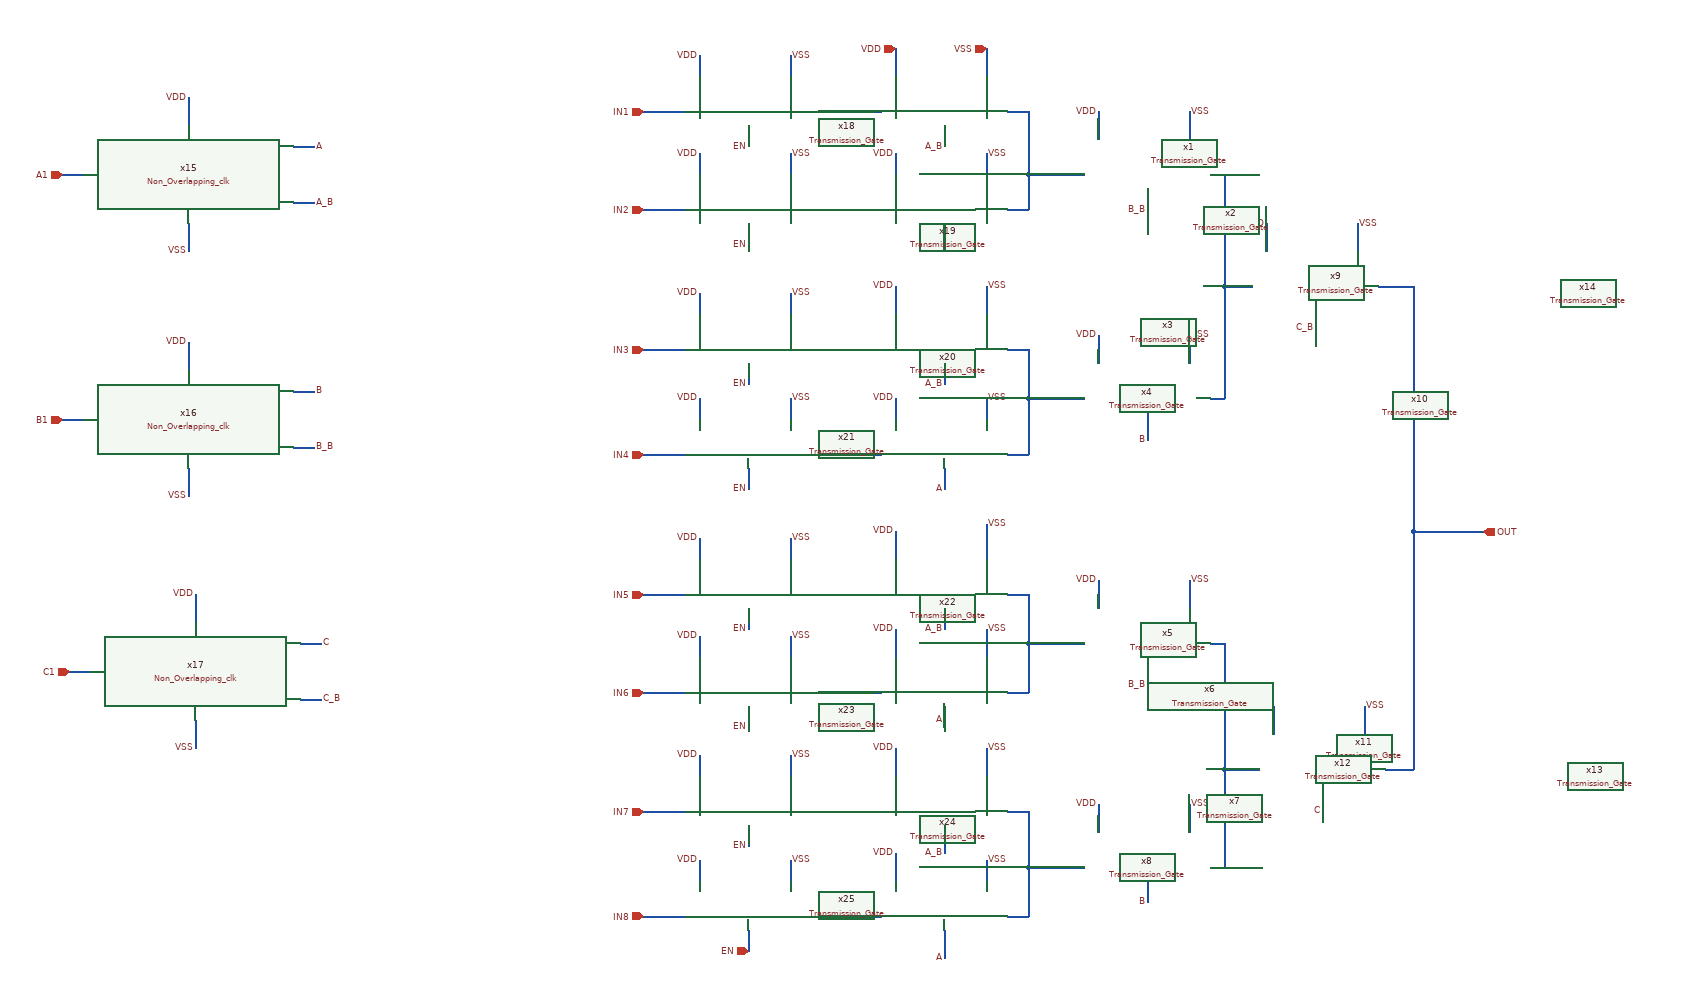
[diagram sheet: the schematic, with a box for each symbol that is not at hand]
v {xschem version=3.1.0 file_version=1.2
}
G {}
K {}
V {}
S {}
E {}
N -810 -1250 -750 -1250 {
lab=IN1}
N -450 -1340 -450 -1300 {
lab=VDD}
N -320 -1340 -320 -1300 {
lab=VSS}
N -450 -1190 -450 -1160 {
lab=VDD}
N -320 -1190 -320 -1160 {
lab=VSS}
N -450 -1000 -450 -960 {
lab=VDD}
N -320 -1000 -320 -960 {
lab=VSS}
N -450 -840 -450 -810 {
lab=VDD}
N -320 -840 -320 -810 {
lab=VSS}
N -380 -1230 -380 -1200 {
lab=A_B}
N -380 -1090 -380 -1050 {
lab=A}
N -380 -890 -380 -860 {
lab=A_B}
N -380 -740 -380 -710 {
lab=A}
N -290 -1250 -260 -1250 {
lab=#net1}
N -290 -1110 -260 -1110 {
lab=#net1}
N -260 -1160 -260 -1110 {
lab=#net1}
N -260 -1160 -180 -1160 {
lab=#net1}
N -290 -910 -260 -910 {
lab=#net2}
N -260 -840 -260 -760 {
lab=#net2}
N -290 -760 -260 -760 {
lab=#net2}
N 0 -1160 20 -1160 {
lab=#net3}
N 20 -1000 20 -840 {
lab=#net3}
N 0 -840 20 -840 {
lab=#net3}
N 20 -1000 60 -1000 {
lab=#net3}
N -290 -560 -260 -560 {
lab=#net4}
N -260 -490 -260 -420 {
lab=#net4}
N -290 -420 -260 -420 {
lab=#net4}
N -260 -490 -180 -490 {
lab=#net4}
N 0 -490 20 -490 {
lab=#net5}
N 20 -310 20 -170 {
lab=#net5}
N 0 -170 20 -170 {
lab=#net5}
N 20 -310 70 -310 {
lab=#net5}
N -290 -250 -260 -250 {
lab=#net6}
N -260 -170 -260 -100 {
lab=#net6}
N -290 -100 -260 -100 {
lab=#net6}
N -260 -170 -180 -170 {
lab=#net6}
N 240 -1000 290 -1000 {
lab=OUT}
N 290 -650 290 -310 {
lab=OUT}
N 250 -310 290 -310 {
lab=OUT}
N 290 -650 390 -650 {
lab=OUT}
N -450 -650 -450 -610 {
lab=VDD}
N -320 -660 -320 -610 {
lab=VSS}
N -380 -540 -380 -510 {
lab=A_B}
N -450 -510 -450 -470 {
lab=VDD}
N -320 -510 -320 -470 {
lab=VSS}
N -380 -400 -380 -370 {
lab=A}
N -450 -340 -450 -300 {
lab=VDD}
N -320 -340 -320 -300 {
lab=VSS}
N -380 -230 -380 -190 {
lab=A_B}
N -380 -80 -380 -40 {
lab=A}
N -450 -190 -450 -150 {
lab=VDD}
N -320 -180 -320 -150 {
lab=VSS}
N -30 -260 -30 -220 {
lab=VSS}
N -160 -260 -160 -220 {
lab=VDD}
N -90 -150 -90 -120 {
lab=B}
N -90 -470 -90 -430 {
lab=B_B}
N -160 -580 -160 -540 {
lab=VDD}
N -30 -580 -30 -540 {
lab=VSS}
N 90 -400 90 -360 {
lab=VDD}
N 220 -400 220 -360 {
lab=VSS}
N 160 -290 160 -250 {
lab=C}
N -160 -1250 -160 -1210 {
lab=VDD}
N -30 -1250 -30 -1210 {
lab=VSS}
N -90 -1140 -90 -1110 {
lab=B_B}
N 80 -1090 80 -1050 {
lab=VDD}
N 210 -1090 210 -1050 {
lab=VSS}
N 150 -980 150 -940 {
lab=C_B}
N -30 -930 -30 -890 {
lab=VSS}
N -160 -930 -160 -890 {
lab=VDD}
N -90 -820 -90 -780 {
lab=B}
N -810 -1110 -750 -1110 {
lab=IN2}
N -810 -910 -750 -910 {
lab=IN3}
N -1460 -1270 -1460 -1230 {
lab=VDD}
N -1460 -1090 -1460 -1050 {
lab=VSS}
N -1310 -1200 -1280 -1200 {
lab=A}
N -1310 -1120 -1280 -1120 {
lab=A_B}
N -1640 -1160 -1610 -1160 {
lab=A1}
N -1460 -920 -1460 -880 {
lab=VDD}
N -1460 -740 -1460 -700 {
lab=VSS}
N -1310 -850 -1280 -850 {
lab=B}
N -1310 -770 -1280 -770 {
lab=B_B}
N -1640 -810 -1610 -810 {
lab=B1}
N -1450 -560 -1450 -520 {
lab=VDD}
N -1450 -380 -1450 -340 {
lab=VSS}
N -1300 -490 -1270 -490 {
lab=C}
N -1300 -410 -1270 -410 {
lab=C_B}
N -1630 -450 -1600 -450 {
lab=C1}
N -810 -760 -750 -760 {
lab=IN4}
N -260 -1250 -260 -1160 {
lab=#net1}
N -260 -910 -260 -840 {
lab=#net2}
N -260 -840 -180 -840 {
lab=#net2}
N 20 -1160 20 -1000 {
lab=#net3}
N -260 -560 -260 -490 {
lab=#net4}
N 20 -490 20 -310 {
lab=#net5}
N -260 -250 -260 -170 {
lab=#net6}
N 290 -1000 290 -650 {
lab=OUT}
N -570 -1250 -470 -1250 {
lab=#net7}
N -730 -1330 -730 -1300 {
lab=VDD}
N -600 -1330 -600 -1300 {
lab=VSS}
N -660 -1230 -660 -1200 {
lab=EN}
N -570 -1110 -470 -1110 {
lab=#net8}
N -730 -1190 -730 -1160 {
lab=VDD}
N -600 -1190 -600 -1160 {
lab=VSS}
N -660 -1090 -660 -1060 {
lab=EN}
N -570 -910 -470 -910 {
lab=#net9}
N -730 -990 -730 -960 {
lab=VDD}
N -600 -990 -600 -960 {
lab=VSS}
N -660 -890 -660 -860 {
lab=EN}
N -570 -760 -470 -760 {
lab=#net10}
N -730 -840 -730 -810 {
lab=VDD}
N -600 -840 -600 -810 {
lab=VSS}
N -660 -740 -660 -710 {
lab=EN}
N -570 -560 -470 -560 {
lab=#net11}
N -730 -640 -730 -610 {
lab=VDD}
N -600 -640 -600 -610 {
lab=VSS}
N -660 -540 -660 -510 {
lab=EN}
N -570 -420 -470 -420 {
lab=#net12}
N -730 -500 -730 -470 {
lab=VDD}
N -600 -500 -600 -470 {
lab=VSS}
N -660 -400 -660 -370 {
lab=EN}
N -570 -250 -470 -250 {
lab=#net13}
N -730 -330 -730 -300 {
lab=VDD}
N -600 -330 -600 -300 {
lab=VSS}
N -660 -230 -660 -200 {
lab=EN}
N -570 -100 -470 -100 {
lab=#net14}
N -730 -180 -730 -150 {
lab=VDD}
N -600 -180 -600 -150 {
lab=VSS}
N -660 -80 -660 -50 {
lab=IN8}
N -810 -560 -750 -560 {
lab=IN5}
N -810 -420 -750 -420 {
lab=IN6}
N -810 -250 -750 -250 {
lab=IN7}
N -810 -100 -750 -100 {
lab=IN8}
C {devices/lab_pin.sym} -450 -1190 0 0 {name=p3 sig_type=std_logic lab=VDD}
C {devices/lab_pin.sym} -450 -1000 0 0 {name=p4 sig_type=std_logic lab=VDD}
C {devices/lab_pin.sym} -160 -1250 0 0 {name=p5 sig_type=std_logic lab=VDD}
C {devices/lab_pin.sym} -450 -840 0 0 {name=p6 sig_type=std_logic lab=VDD}
C {devices/lab_pin.sym} -450 -650 0 0 {name=p7 sig_type=std_logic lab=VDD}
C {devices/lab_pin.sym} -160 -580 0 0 {name=p8 sig_type=std_logic lab=VDD}
C {devices/lab_pin.sym} -450 -510 0 0 {name=p9 sig_type=std_logic lab=VDD}
C {devices/lab_pin.sym} -450 -340 0 0 {name=p10 sig_type=std_logic lab=VDD}
C {devices/lab_pin.sym} -450 -190 0 0 {name=p11 sig_type=std_logic lab=VDD}
C {devices/lab_pin.sym} -160 -260 0 0 {name=p12 sig_type=std_logic lab=VDD}
C {devices/lab_pin.sym} 90 -400 0 0 {name=p13 sig_type=std_logic lab=VDD}
C {devices/lab_pin.sym} -160 -930 0 0 {name=p14 sig_type=std_logic lab=VDD}
C {devices/lab_pin.sym} 80 -1090 0 0 {name=p15 sig_type=std_logic lab=VDD}
C {devices/lab_pin.sym} -320 -1190 2 0 {name=p16 sig_type=std_logic lab=VSS}
C {devices/lab_pin.sym} -30 -1250 2 0 {name=p17 sig_type=std_logic lab=VSS}
C {devices/lab_pin.sym} 210 -1090 2 0 {name=p18 sig_type=std_logic lab=VSS}
C {devices/lab_pin.sym} -30 -930 2 0 {name=p19 sig_type=std_logic lab=VSS}
C {devices/lab_pin.sym} -320 -1000 2 0 {name=p20 sig_type=std_logic lab=VSS}
C {devices/lab_pin.sym} -320 -840 2 0 {name=p21 sig_type=std_logic lab=VSS}
C {devices/lab_pin.sym} -320 -660 2 0 {name=p22 sig_type=std_logic lab=VSS}
C {devices/lab_pin.sym} -30 -580 2 0 {name=p23 sig_type=std_logic lab=VSS}
C {devices/lab_pin.sym} -320 -510 2 0 {name=p24 sig_type=std_logic lab=VSS}
C {devices/lab_pin.sym} 220 -400 2 0 {name=p25 sig_type=std_logic lab=VSS}
C {devices/lab_pin.sym} -320 -340 2 0 {name=p26 sig_type=std_logic lab=VSS}
C {devices/lab_pin.sym} -320 -180 2 0 {name=p27 sig_type=std_logic lab=VSS}
C {devices/lab_pin.sym} -30 -260 2 0 {name=p28 sig_type=std_logic lab=VSS}
C {devices/lab_pin.sym} -1460 -1270 1 0 {name=p29 sig_type=std_logic lab=VDD}
C {devices/lab_pin.sym} -1460 -1050 3 0 {name=p30 sig_type=std_logic lab=VSS}
C {devices/lab_pin.sym} -1460 -920 1 0 {name=p31 sig_type=std_logic lab=VDD}
C {devices/lab_pin.sym} -1460 -700 3 0 {name=p32 sig_type=std_logic lab=VSS}
C {devices/lab_pin.sym} -1450 -560 1 0 {name=p33 sig_type=std_logic lab=VDD}
C {devices/lab_pin.sym} -1450 -340 3 0 {name=p34 sig_type=std_logic lab=VSS}
C {devices/opin.sym} 390 -650 0 0 {name=p35 lab=OUT}
C {devices/iopin.sym} -450 -1340 2 0 {name=p1 lab=VDD}
C {devices/iopin.sym} -320 -1340 0 0 {name=p2 lab=VSS}
C {devices/ipin.sym} -810 -1250 0 0 {name=p36 lab=IN1}
C {devices/ipin.sym} -810 -1110 0 0 {name=p37 lab=IN2}
C {devices/ipin.sym} -810 -910 0 0 {name=p38 lab=IN3
}
C {devices/ipin.sym} -810 -760 0 0 {name=p39 lab=IN4}
C {devices/ipin.sym} -810 -560 0 0 {name=p40 lab=IN5}
C {devices/ipin.sym} -810 -420 0 0 {name=p41 lab=IN6}
C {devices/ipin.sym} -810 -250 0 0 {name=p42 lab=IN7}
C {devices/ipin.sym} -810 -100 0 0 {name=p43 lab=IN8}
C {devices/ipin.sym} -1640 -1160 0 0 {name=p44 lab=A1
}
C {devices/ipin.sym} -1640 -810 0 0 {name=p45 lab=B1}
C {devices/ipin.sym} -1630 -450 0 0 {name=p46 lab=C1}
C {devices/lab_pin.sym} -380 -1200 3 0 {name=p53 sig_type=std_logic lab=A_B}
C {devices/lab_pin.sym} -380 -1060 3 0 {name=p54 sig_type=std_logic lab=A}
C {devices/lab_pin.sym} -90 -780 3 0 {name=p57 sig_type=std_logic lab=B}
C {devices/lab_pin.sym} -90 -1110 3 0 {name=p58 sig_type=std_logic lab=B_B}
C {devices/lab_pin.sym} 150 -940 3 0 {name=p59 sig_type=std_logic lab=C_B}
C {devices/lab_pin.sym} 160 -250 3 0 {name=p63 sig_type=std_logic lab=C}
C {devices/lab_pin.sym} -380 -860 3 0 {name=p55 sig_type=std_logic lab=A_B}
C {devices/lab_pin.sym} -380 -710 3 0 {name=p56 sig_type=std_logic lab=A}
C {devices/lab_pin.sym} -380 -510 3 0 {name=p60 sig_type=std_logic lab=A_B}
C {devices/lab_pin.sym} -380 -380 3 0 {name=p61 sig_type=std_logic lab=A}
C {devices/lab_pin.sym} -380 -190 3 0 {name=p65 sig_type=std_logic lab=A_B}
C {devices/lab_pin.sym} -90 -120 3 0 {name=p62 sig_type=std_logic lab=B}
C {devices/lab_pin.sym} -90 -430 3 0 {name=p64 sig_type=std_logic lab=B_B}
C {devices/lab_pin.sym} -1280 -1200 2 0 {name=p47 sig_type=std_logic lab=A}
C {devices/lab_pin.sym} -1280 -1120 2 0 {name=p48 sig_type=std_logic lab=A_B}
C {devices/lab_pin.sym} -1280 -850 2 0 {name=p49 sig_type=std_logic lab=B}
C {devices/lab_pin.sym} -1280 -770 2 0 {name=p50 sig_type=std_logic lab=B_B}
C {devices/lab_pin.sym} -1270 -410 2 0 {name=p52 sig_type=std_logic lab=C_B}
C {devices/lab_pin.sym} -1270 -490 2 0 {name=p67 sig_type=std_logic lab=C}
C {devices/lab_pin.sym} -380 -40 3 0 {name=p51 sig_type=std_logic lab=A}
C {/home/shahid/GF180Projects/Tapeout/Xschem/Logic_Gates/Transmission_Gate.sym} 10 -1240 0 0 {name=x1}
C {/home/shahid/GF180Projects/Tapeout/Xschem/Logic_Gates/Transmission_Gate.sym} 10 -1100 0 0 {name=x2}
C {/home/shahid/GF180Projects/Tapeout/Xschem/Logic_Gates/Transmission_Gate.sym} 10 -900 0 0 {name=x3}
C {/home/shahid/GF180Projects/Tapeout/Xschem/Logic_Gates/Transmission_Gate.sym} 10 -750 0 0 {name=x4}
C {/home/shahid/GF180Projects/Tapeout/Xschem/Logic_Gates/Transmission_Gate.sym} 10 -550 0 0 {name=x5}
C {/home/shahid/GF180Projects/Tapeout/Xschem/Logic_Gates/Transmission_Gate.sym} 10 -410 0 0 {name=x6}
C {/home/shahid/GF180Projects/Tapeout/Xschem/Logic_Gates/Transmission_Gate.sym} 10 -240 0 0 {name=x7}
C {/home/shahid/GF180Projects/Tapeout/Xschem/Logic_Gates/Transmission_Gate.sym} 10 -90 0 0 {name=x8}
C {/home/shahid/GF180Projects/Tapeout/Xschem/Logic_Gates/Transmission_Gate.sym} 300 -1150 0 0 {name=x9}
C {/home/shahid/GF180Projects/Tapeout/Xschem/Logic_Gates/Transmission_Gate.sym} 300 -830 0 0 {name=x10}
C {/home/shahid/GF180Projects/Tapeout/Xschem/Logic_Gates/Transmission_Gate.sym} 300 -480 0 0 {name=x11}
C {/home/shahid/GF180Projects/Tapeout/Xschem/Logic_Gates/Transmission_Gate.sym} 300 -160 0 0 {name=x12}
C {/home/shahid/GF180Projects/Tapeout/Xschem/Logic_Gates/Transmission_Gate.sym} 550 -300 0 0 {name=x13}
C {/home/shahid/GF180Projects/Tapeout/Xschem/Logic_Gates/Transmission_Gate.sym} 540 -990 0 0 {name=x14}
C {/home/shahid/GF180Projects/Tapeout/Xschem/Non_OvL_CLK_Gen/Non_Overlapping_clk.sym} -1460 -1160 0 0 {name=x15}
C {/home/shahid/GF180Projects/Tapeout/Xschem/Non_OvL_CLK_Gen/Non_Overlapping_clk.sym} -1460 -810 0 0 {name=x16}
C {/home/shahid/GF180Projects/Tapeout/Xschem/Non_OvL_CLK_Gen/Non_Overlapping_clk.sym} -1450 -450 0 0 {name=x17}
C {/home/shahid/GF180Projects/Tapeout/Xschem/Logic_Gates/Transmission_Gate.sym} -270 -1240 0 0 {name=x18}
C {devices/lab_pin.sym} -730 -1330 0 0 {name=p66 sig_type=std_logic lab=VDD}
C {devices/lab_pin.sym} -600 -1330 2 0 {name=p68 sig_type=std_logic lab=VSS}
C {devices/lab_pin.sym} -660 -1200 3 0 {name=p69 sig_type=std_logic lab=EN}
C {/home/shahid/GF180Projects/Tapeout/Xschem/Logic_Gates/Transmission_Gate.sym} -270 -1100 0 0 {name=x19}
C {devices/lab_pin.sym} -730 -1190 0 0 {name=p70 sig_type=std_logic lab=VDD}
C {devices/lab_pin.sym} -600 -1190 2 0 {name=p71 sig_type=std_logic lab=VSS}
C {devices/lab_pin.sym} -660 -1060 3 0 {name=p72 sig_type=std_logic lab=EN}
C {/home/shahid/GF180Projects/Tapeout/Xschem/Logic_Gates/Transmission_Gate.sym} -270 -900 0 0 {name=x20}
C {devices/lab_pin.sym} -730 -990 0 0 {name=p73 sig_type=std_logic lab=VDD}
C {devices/lab_pin.sym} -600 -990 2 0 {name=p74 sig_type=std_logic lab=VSS}
C {devices/lab_pin.sym} -660 -860 3 0 {name=p75 sig_type=std_logic lab=EN}
C {/home/shahid/GF180Projects/Tapeout/Xschem/Logic_Gates/Transmission_Gate.sym} -270 -750 0 0 {name=x21}
C {devices/lab_pin.sym} -730 -840 0 0 {name=p76 sig_type=std_logic lab=VDD}
C {devices/lab_pin.sym} -600 -840 2 0 {name=p77 sig_type=std_logic lab=VSS}
C {devices/lab_pin.sym} -660 -710 3 0 {name=p78 sig_type=std_logic lab=EN}
C {/home/shahid/GF180Projects/Tapeout/Xschem/Logic_Gates/Transmission_Gate.sym} -270 -550 0 0 {name=x22}
C {devices/lab_pin.sym} -730 -640 0 0 {name=p79 sig_type=std_logic lab=VDD}
C {devices/lab_pin.sym} -600 -640 2 0 {name=p80 sig_type=std_logic lab=VSS}
C {devices/lab_pin.sym} -660 -510 3 0 {name=p81 sig_type=std_logic lab=EN}
C {/home/shahid/GF180Projects/Tapeout/Xschem/Logic_Gates/Transmission_Gate.sym} -270 -410 0 0 {name=x23}
C {devices/lab_pin.sym} -730 -500 0 0 {name=p82 sig_type=std_logic lab=VDD}
C {devices/lab_pin.sym} -600 -500 2 0 {name=p83 sig_type=std_logic lab=VSS}
C {devices/lab_pin.sym} -660 -370 3 0 {name=p84 sig_type=std_logic lab=EN}
C {/home/shahid/GF180Projects/Tapeout/Xschem/Logic_Gates/Transmission_Gate.sym} -270 -240 0 0 {name=x24}
C {devices/lab_pin.sym} -730 -330 0 0 {name=p85 sig_type=std_logic lab=VDD}
C {devices/lab_pin.sym} -600 -330 2 0 {name=p86 sig_type=std_logic lab=VSS}
C {devices/lab_pin.sym} -660 -200 3 0 {name=p87 sig_type=std_logic lab=EN}
C {/home/shahid/GF180Projects/Tapeout/Xschem/Logic_Gates/Transmission_Gate.sym} -270 -90 0 0 {name=x25}
C {devices/lab_pin.sym} -730 -180 0 0 {name=p88 sig_type=std_logic lab=VDD}
C {devices/lab_pin.sym} -600 -180 2 0 {name=p89 sig_type=std_logic lab=VSS}
C {devices/ipin.sym} -660 -50 3 0 {name=p90 lab=EN}
